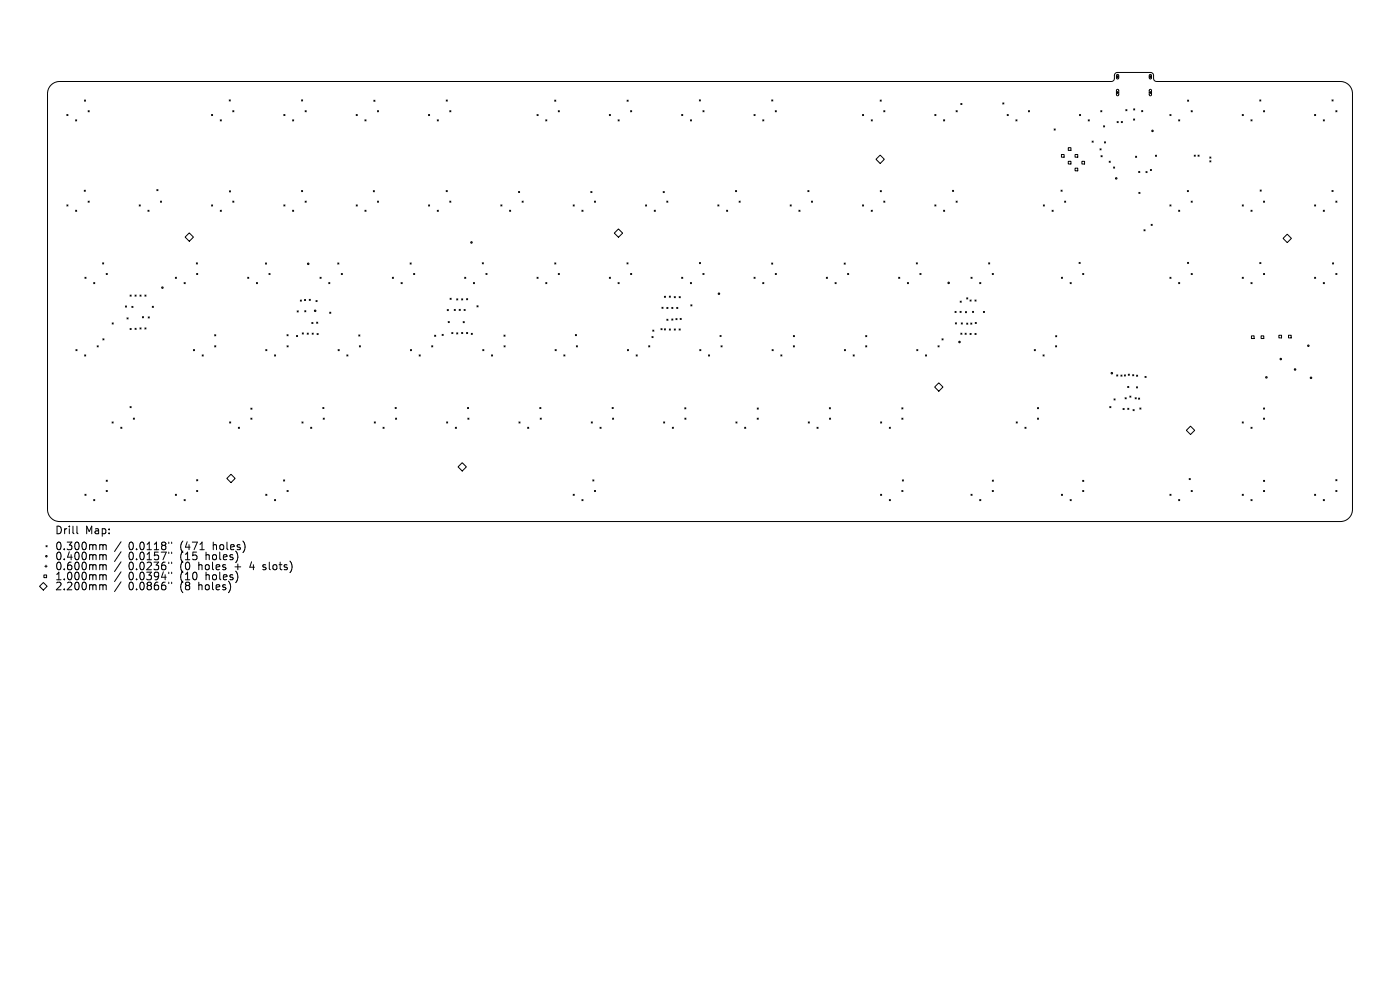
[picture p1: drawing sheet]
<svg xmlns="http://www.w3.org/2000/svg" width="297mm" height="210mm" viewBox="0 0 297 210" stroke-linecap="round" stroke-linejoin="round" font-family="sans-serif">
<defs><g id="words">
<g font-size="2.2">
<text x="11.6" y="113.5">Drill</text>
<text x="18.1" y="113.5">Map:</text>
<text x="11.6" y="116.9">0.300mm</text>
<text x="11.6" y="119">0.400mm</text>
<text x="27.3" y="116.9">0.0118&quot;</text>
<text x="27.3" y="119">0.0157&quot;</text>
<text x="38.3" y="116.9">(471</text>
<text x="38.3" y="119">(15</text>
<text x="43.9" y="119">holes)</text>
<text x="45.4" y="116.9">holes)</text>
<text x="11.6" y="121.2">0.600mm</text>
<text x="11.6" y="123.3">1.000mm</text>
<text x="11.6" y="125.4">2.200mm</text>
<text x="27.3" y="121.2">0.0236&quot;</text>
<text x="27.3" y="123.3">0.0394&quot;</text>
<text x="27.3" y="125.4">0.0866&quot;</text>
<text x="38.3" y="121.2">(0</text>
<text x="38.3" y="123.3">(10</text>
<text x="38.3" y="125.4">(8</text>
<text x="42.3" y="121.2">holes</text>
<text x="42.3" y="125.4">holes)</text>
<text x="43.9" y="123.3">holes)</text>
<text x="50.2" y="121.2">+</text>
<text x="53.5" y="121.2">4</text>
<text x="56.5" y="121.2">slots)</text>
</g>
</g></defs>
<g fill="none" stroke="#000" stroke-width=".21">
<path d="M10.8 18l.7-.5 1.1-.2h223.2l.5-.4 .3-1.3 .5-.2h7.1l.5 .3 .1 1.2 .6 .4h39a2.56 2.56 0 0 1 2.5 2.5v88.3a2.56 2.56 0 0 1-2.5 2.5h-271.8a2.56 2.56 0 0 1-2.5-2.5v-88.3l.1-.8zM236.8 16.3h.5M236.8 19.6h.5M236.9 15.9l.3-.1 .1 .2v.6l-.1 .1-.3-.1zM236.9 19h.3l.1 .2v.9l-.2 .2-.2-.2zM237.1 16v.5M237.1 19.4v.5M243.8 16.3h.5M243.8 19.6h.5M243.9 15.9l.2-.1 .2 .2v.6l-.2 .1-.3-.1zM243.9 19h.2l.2 .2v.9l-.2 .2-.3-.2zM244 16v.5"/>
<path d="M244 19.4v.5M14.2 24.3l.2 .2M14.4 24.3l-.2 .2M16 25.4l.3 .3M16.3 25.4l-.3 .3M17.9 21.2l.3 .3M18.2 21.2l-.3 .3M18.7 23.5l.2 .2M18.9 23.5l-.2 .2M44.9 24.3l.2 .2M45.1 24.3l-.2 .2M46.7 25.4l.3 .3"/>
<path d="M47 25.4l-.3 .3M48.6 21.2l.3 .2M48.9 21.2l-.3 .2M49.4 23.5l.2 .2M49.6 23.5l-.2 .2M60.2 24.3l.3 .2M60.5 24.3l-.3 .2M62.1 25.4l.2 .3M62.3 25.4l-.2 .3M64 21.2l.2 .2M64.2 21.2l-.2 .2M64.7 23.5l.3 .2"/>
<path d="M65 23.5l-.3 .2M75.6 24.3l.2 .2M75.8 24.3l-.2 .2M77.4 25.4l.3 .3M77.7 25.4l-.3 .3M79.3 21.3l.3 .2M79.6 21.3l-.3 .2M80.1 23.5l.2 .2M80.3 23.5l-.2 .2M90.9 24.3l.2 .2M91.1 24.3l-.2 .2M92.8 25.4l.2 .3"/>
<path d="M93 25.4l-.2 .3M94.7 21.2l.2 .3M94.9 21.2l-.2 .3M95.4 23.5l.3 .2M95.7 23.5l-.3 .2M113.9 24.3l.3 .2M114.2 24.3l-.3 .2M115.8 25.4l.2 .3M116 25.4l-.2 .3M117.7 21.2l.2 .3M117.9 21.2l-.2 .3M118.4 23.5l.3 .2"/>
<path d="M118.7 23.5l-.3 .2M129.3 24.3l.2 .2M129.5 24.3l-.2 .2M131.1 25.4l.3 .3M131.4 25.4l-.3 .3M133 21.2l.3 .3M133.3 21.2l-.3 .3M133.8 23.5l.2 .2M134 23.5l-.2 .2M144.6 24.3l.3 .2M144.9 24.3l-.3 .2M146.5 25.4l.2 .3"/>
<path d="M146.7 25.4l-.2 .3M148.4 21.2l.2 .2M148.6 21.2l-.2 .2M149.1 23.5l.3 .2M149.4 23.5l-.3 .2M160 24.3l.2 .2M160.2 24.3l-.2 .2M161.8 25.4l.2 .3M162 25.4l-.2 .3M163.7 21.2l.3 .2M164 21.2l-.3 .2M164.5 23.5l.2 .2"/>
<path d="M164.7 23.5l-.2 .2M183 24.3l.2 .2M183.2 24.3l-.2 .2M184.8 25.4l.3 .3M185.1 25.4l-.3 .3M185.8 33.8l.9-.9 .9 .9-.9 .9zM186.7 21.2l.3 .3M187 21.2l-.3 .3M187.5 23.5l.2 .2M187.7 23.5l-.2 .2M198.3 24.3l.3 .2M198.6 24.3l-.3 .2"/>
<path d="M200.2 25.4l.2 .3M200.4 25.4l-.2 .3M202.8 23.5l.3 .2M203.1 23.5l-.3 .2M203.8 21.9l.3 .3M204.1 21.9l-.3 .3M212.7 21.8l.3 .3M213 21.8l-.3 .3M213.7 24.3l.2 .2M213.9 24.3l-.2 .2M215.5 25.4l.3 .3M215.8 25.4l-.3 .3"/>
<path d="M218.2 23.5l.2 .2M218.4 23.5l-.2 .2M223.6 27.4l.3 .2M223.9 27.4l-.3 .2M225.2 32.8h.5v.5h-.5zM226.6 31.3h.6v.6h-.6zM226.6 34.2h.6v.6h-.6zM228.1 32.8h.5v.5h-.5zM228.1 35.7h.5v.5h-.5zM229 24.3l.2 .2M229.2 24.3l-.2 .2M229.5 34.2h.6v.6h-.6z"/>
<path d="M230.9 25.4l.2 .3M231.1 25.4l-.2 .3M231.7 29.9l.2 .3M231.9 29.9l-.2 .3M233.4 31.6l.2 .2M233.5 23.5l.3 .2M233.6 33l.2 .3M233.6 31.6l-.2 .2M233.8 23.5l-.3 .2M233.8 33l-.2 .3M234.1 26.7l.2 .2M234.3 30.1l.2 .2"/>
<path d="M234.3 26.7l-.2 .2M234.5 30.1l-.2 .2M235.3 34.2l.2 .2M235.5 34.2l-.2 .2M236.2 35.4l.3 .3M236.5 35.4l-.3 .3M237 25.8l.2 .2M237.2 25.8l-.2 .2M237.9 25.8l.2 .2M238.1 25.8l-.2 .2M238.8 23.3l.3 .2M239.1 23.3l-.3 .2"/>
<path d="M240.5 25.2l.2 .3M240.5 23.1l.2 .2M240.7 25.2l-.2 .3M240.7 23.1l-.2 .2M240.9 33.1l.2 .3M241.1 33.1l-.2 .3M241.6 36.4l.2 .2M241.8 36.4l-.2 .2M242.2 23.5l.2 .2M242.4 23.5l-.2 .2M243.1 36.4l.3 .2M243.4 36.4l-.3 .2"/>
<path d="M244 35.9l.3 .3M244.3 35.9l-.3 .3M245.1 32.9l.3 .3M245.4 32.9l-.3 .3M248.2 24.3l.2 .2M248.4 24.3l-.2 .2M250 25.4l.3 .3M250.3 25.4l-.3 .3M251.9 21.2l.3 .3M252.2 21.2l-.3 .3M252.7 23.5l.2 .2M252.9 23.5l-.2 .2"/>
<path d="M253.3 32.9l.3 .2M253.6 32.9l-.3 .2M254.2 32.9l.2 .2M254.4 32.9l-.2 .2M256.6 33.3l.3 .2M256.6 34.1l.3 .3M256.9 33.3l-.3 .2M256.9 34.1l-.3 .3M263.5 24.3l.3 .2M263.8 24.3l-.3 .2M265.4 25.4l.2 .3M265.6 25.4l-.2 .3"/>
<path d="M267.2 21.2l.3 .2M267.5 21.2l-.3 .2M268 23.5l.3 .2M268.3 23.5l-.3 .2M278.9 24.3l.2 .2M279.1 24.3l-.2 .2M280.7 25.4l.3 .3M281 25.4l-.3 .3M282.6 21.2l.2 .2M282.8 21.2l-.2 .2M283.4 23.5l.2 .2M283.6 23.5l-.2 .2"/>
<path d="M14.2 43.5l.2 .2M14.4 43.5l-.2 .2M16 44.6l.3 .2M16.3 44.6l-.3 .2M17.9 40.3l.2 .3M18 58.8l.3 .3M18.1 40.3l-.2 .3M18.3 58.8l-.3 .3M18.7 42.7l.2 .2M18.9 42.7l-.2 .2M19.9 59.9l.2 .3M20.1 59.9l-.2 .3"/>
<path d="M21.8 55.8l.2 .2M22 55.8l-.2 .2M22.5 58l.3 .2M22.8 58l-.3 .2M29.5 43.5l.3 .2M29.8 43.5l-.3 .2M31.4 44.6l.2 .2M31.6 44.6l-.2 .2M33.3 40.2l.2 .3M33.5 40.2l-.2 .3M34 42.7l.3 .2M34.3 42.7l-.3 .2"/>
<path d="M37.2 58.8l.2 .3M37.4 58.8l-.2 .3M39.1 59.9l.2 .3M39.3 59.9l-.2 .3M40.2 49.4l.8 .9-.8 .9-.9-.9zM41.6 55.8l.3 .2M41.7 58l.3 .2M41.9 55.8l-.3 .2M42 58l-.3 .2M44.9 43.5l.2 .2M45.1 43.5l-.2 .2M46.7 44.6l.3 .2"/>
<path d="M47 44.6l-.3 .2M48.7 40.5l.2 .2M48.9 40.5l-.2 .2M49.4 42.7l.2 .2M49.6 42.7l-.2 .2M52.5 58.8l.3 .3M52.8 58.8l-.3 .3M54.4 59.9l.2 .3M54.6 59.9l-.2 .3M56.3 55.8l.2 .2M56.5 55.8l-.2 .2M57.1 58l.2 .2"/>
<path d="M57.3 58l-.2 .2M60.2 43.5l.3 .2M60.5 43.5l-.3 .2M62.1 44.6l.2 .2M62.3 44.6l-.2 .2M64 40.4l.2 .3M64.2 40.4l-.2 .3M64.7 42.7l.3 .2M65 42.7l-.3 .2M67.9 58.8l.2 .3M68.1 58.8l-.2 .3M69.7 59.9l.3 .3"/>
<path d="M70 59.9l-.3 .3M71.7 55.8l.2 .2M71.9 55.8l-.2 .2M72.4 58l.2 .2M72.6 58l-.2 .2M75.6 43.5l.2 .2M75.8 43.5l-.2 .2M77.4 44.6l.3 .2M77.7 44.6l-.3 .2M79.2 40.4l.2 .3M79.4 40.4l-.2 .3M80.1 42.7l.2 .2"/>
<path d="M80.3 42.7l-.2 .2M83.2 58.8l.3 .3M83.5 58.8l-.3 .3M85.1 59.9l.2 .3M85.3 59.9l-.2 .3M87 55.8l.2 .2M87.2 55.8l-.2 .2M87.7 58l.3 .2M88 58l-.3 .2M90.9 43.5l.2 .2M91.1 43.5l-.2 .2M92.8 44.6l.2 .2"/>
<path d="M93 44.6l-.2 .2M94.7 40.4l.2 .3M94.9 40.4l-.2 .3M95.4 42.7l.3 .2M95.7 42.7l-.3 .2M98.6 58.8l.2 .3M98.8 58.8l-.2 .3M100.4 59.9l.3 .3M100.7 59.9l-.3 .3M102.3 55.7l.3 .3M102.6 55.7l-.3 .3M103.1 58l.2 .2"/>
<path d="M103.3 58l-.2 .2M106.2 43.5l.3 .2M106.5 43.5l-.3 .2M108.1 44.6l.2 .2M108.3 44.6l-.2 .2M110 40.6l.2 .3M110.2 40.6l-.2 .3M110.8 42.7l.2 .2M111 42.7l-.2 .2M113.9 58.8l.3 .3M114.2 58.8l-.3 .3M115.8 59.9l.2 .3"/>
<path d="M116 59.9l-.2 .3M117.7 55.8l.2 .2M117.9 55.8l-.2 .2M118.4 58l.3 .2M118.7 58l-.3 .2M121.6 43.5l.2 .2M121.8 43.5l-.2 .2M123.4 44.6l.3 .2M123.7 44.6l-.3 .2M125.3 40.6l.3 .3M125.6 40.6l-.3 .3M126.1 42.7l.2 .2"/>
<path d="M126.3 42.7l-.2 .2M129.3 58.8l.2 .3M129.5 58.8l-.2 .3M131.1 59.9l.3 .3M131.2 48.6l.9 .8-.9 .9-.9-.9zM131.4 59.9l-.3 .3M133 55.8l.2 .2M133.2 55.8l-.2 .2M133.8 58l.2 .2M134 58l-.2 .2M136.9 43.5l.3 .2M137.2 43.5l-.3 .2"/>
<path d="M138.8 44.6l.2 .2M139 44.6l-.2 .2M140.7 40.6l.2 .3M140.9 40.6l-.2 .3M141.4 42.7l.3 .2M141.7 42.7l-.3 .2M144.6 58.8l.3 .3M144.9 58.8l-.3 .3M146.5 59.9l.2 .3M146.7 59.9l-.2 .3M148.4 55.7l.2 .2M148.6 55.7l-.2 .2"/>
<path d="M149.1 58l.3 .2M149.4 58l-.3 .2M152.3 43.5l.2 .2M152.5 43.5l-.2 .2M154.1 44.6l.3 .2M154.4 44.6l-.3 .2M156 40.4l.3 .3M156.3 40.4l-.3 .3M156.8 42.7l.2 .2M157 42.7l-.2 .2M160 58.8l.2 .3M160.2 58.8l-.2 .3"/>
<path d="M161.8 59.9l.2 .3M162 59.9l-.2 .3M163.7 55.8l.2 .2M163.9 55.8l-.2 .2M164.5 58l.2 .2M164.7 58l-.2 .2M167.6 43.5l.3 .2M167.9 43.5l-.3 .2M169.5 44.6l.2 .2M169.7 44.6l-.2 .2M171.4 40.4l.2 .3M171.6 40.4l-.2 .3"/>
<path d="M172.1 42.7l.3 .2M172.4 42.7l-.3 .2M175.3 58.8l.2 .3M175.5 58.8l-.2 .3M177.2 59.9l.2 .3M177.4 59.9l-.2 .3M179.1 55.8l.2 .2M179.3 55.8l-.2 .2M179.8 58l.3 .2M180.1 58l-.3 .2M183 43.5l.2 .2M183.2 43.5l-.2 .2"/>
<path d="M184.8 44.6l.3 .2M185.1 44.6l-.3 .2M186.7 40.4l.3 .3M187 40.4l-.3 .3M187.5 42.7l.2 .2M187.7 42.7l-.2 .2M190.6 58.8l.3 .3M190.9 58.8l-.3 .3M192.5 59.9l.2 .3M192.7 59.9l-.2 .3M194.4 55.8l.2 .2M194.6 55.8l-.2 .2"/>
<path d="M195.2 58l.2 .2M195.4 58l-.2 .2M198.3 43.5l.3 .2M198.6 43.5l-.3 .2M200.2 44.6l.2 .2M200.4 44.6l-.2 .2M202.1 40.4l.2 .2M202.3 40.4l-.2 .2M202.8 42.7l.3 .2M203.1 42.7l-.3 .2M206 58.8l.2 .3M206.2 58.8l-.2 .3"/>
<path d="M207.8 59.9l.3 .3M208.1 59.9l-.3 .3M209.7 55.8l.3 .2M210 55.8l-.3 .2M210.5 58l.2 .2M210.7 58l-.2 .2M221.3 43.5l.3 .2M221.6 43.5l-.3 .2M223.2 44.6l.2 .2M223.4 44.6l-.2 .2M225.1 40.3l.2 .3M225.2 58.8l.2 .3"/>
<path d="M225.3 40.3l-.2 .3M225.4 58.8l-.2 .3M225.8 42.7l.3 .2M226.1 42.7l-.3 .2M227 59.9l.3 .3M227.3 59.9l-.3 .3M228.9 55.7l.3 .2M229.2 55.7l-.3 .2M229.7 58l.2 .2M229.9 58l-.2 .2M241.6 40.8l.2 .2M241.8 40.8l-.2 .2"/>
<path d="M242.7 48.7l.2 .3M242.9 48.7l-.2 .3M244.2 47.6l.2 .2M244.4 47.6l-.2 .2M248.2 43.5l.2 .2M248.2 58.8l.2 .3M248.4 43.5l-.2 .2M248.4 58.8l-.2 .3M250 44.6l.3 .2M250 59.9l.3 .3M250.3 44.6l-.3 .2M250.3 59.9l-.3 .3"/>
<path d="M251.9 40.4l.2 .3M251.9 55.7l.3 .2M252.1 40.4l-.2 .3M252.2 55.7l-.3 .2M252.7 42.7l.2 .2M252.7 58l.2 .2M252.9 42.7l-.2 .2M252.9 58l-.2 .2M263.5 43.5l.3 .2M263.5 58.8l.3 .3M263.8 43.5l-.3 .2M263.8 58.8l-.3 .3"/>
<path d="M265.4 44.6l.2 .2M265.4 59.9l.2 .3M265.6 44.6l-.2 .2M265.6 59.9l-.2 .3M267.3 55.7l.2 .2M267.3 40.3l.3 .2M267.5 55.7l-.2 .2M267.6 40.3l-.3 .2M268 42.7l.3 .2M268 58l.3 .2M268.3 42.7l-.3 .2M268.3 58l-.3 .2"/>
<path d="M272.2 50.6l.9-.9 .9 .9-.9 .9zM278.9 43.5l.2 .2M278.9 58.8l.2 .3M279.1 43.5l-.2 .2M279.1 58.8l-.2 .3M280.7 44.6l.3 .2M280.7 59.9l.3 .3M281 44.6l-.3 .2M281 59.9l-.3 .3M282.6 40.4l.2 .2M282.7 55.8l.2 .2M282.8 40.4l-.2 .2"/>
<path d="M282.9 55.8l-.2 .2M283.4 58l.2 .2M283.4 42.7l.2 .2M283.6 42.7l-.2 .2M283.6 58l-.2 .2M16.1 74.2l.2 .2M16.3 74.2l-.2 .2M18 75.3l.2 .2M18.2 75.3l-.2 .2M20.6 73.4l.3 .2M20.9 73.4l-.3 .2M21.8 71.9l.3 .2"/>
<path d="M22.1 71.9l-.3 .2M23.8 68.5l.2 .2M24 68.5l-.2 .2M26.6 64.9l.2 .2M26.8 64.9l-.2 .2M26.9 67.4l.3 .3M27.2 67.4l-.3 .3M27.6 62.6l.2 .2M27.6 69.7l.2 .2M27.8 62.6l-.2 .2M27.8 69.7l-.2 .2M28 65l.2 .2"/>
<path d="M28.2 65l-.2 .2M28.6 62.6l.3 .2M28.6 69.6l.3 .3M28.9 62.6l-.3 .2M28.9 69.6l-.3 .3M29.7 62.6l.2 .2M29.7 69.6l.2 .2M29.9 62.6l-.2 .2M29.9 69.6l-.2 .2M30.2 67.2l.3 .2M30.5 67.2l-.3 .2M30.7 62.6l.3 .2"/>
<path d="M30.7 69.6l.3 .2M31 62.6l-.3 .2M31 69.6l-.3 .2M31.4 67.2l.3 .3M31.7 67.2l-.3 .3M32.3 65l.2 .2M32.5 65l-.2 .2M41 74.2l.3 .2M41.3 74.2l-.3 .2M42.9 75.3l.2 .2M43.1 75.3l-.2 .2M45.5 71l.3 .2"/>
<path d="M45.5 73.4l.3 .2M45.8 71l-.3 .2M45.8 73.4l-.3 .2M56.4 74.2l.2 .2M56.6 74.2l-.2 .2M58.2 75.3l.3 .2M58.5 75.3l-.3 .2M60.9 71l.2 .2M60.9 73.4l.2 .2M61.1 71l-.2 .2M61.1 73.4l-.2 .2M62.9 71.2l.2 .2"/>
<path d="M63 65.9l.3 .3M63.1 71.2l-.2 .2M63.3 65.9l-.3 .3M63.7 63.7l.3 .2M64 63.7l-.3 .2M64.1 70.6l.3 .3M64.4 70.6l-.3 .3M64.6 63.5l.2 .3M64.6 65.9l.3 .3M64.8 63.5l-.2 .3M64.9 65.9l-.3 .3M65.2 70.7l.2 .2"/>
<path d="M65.4 70.7l-.2 .2M65.6 63.5l.2 .2M65.8 63.5l-.2 .2M66.2 68.4l.2 .2M66.2 70.7l.3 .2M66.4 68.4l-.2 .2M66.5 70.7l-.3 .2M67 63.7l.3 .3M67.2 68.3l.2 .3M67.3 70.7l.2 .3M67.3 63.7l-.3 .3M67.4 68.3l-.2 .3"/>
<path d="M67.5 70.7l-.2 .3M69.9 66.2l.3 .3M70.2 66.2l-.3 .3M71.7 74.2l.3 .2M72 74.2l-.3 .2M73.6 75.3l.2 .2M73.8 75.3l-.2 .2M76.1 71l.2 .3M76.2 73.4l.3 .2M76.3 71l-.2 .3M76.5 73.4l-.3 .2M87.1 74.2l.2 .2"/>
<path d="M87.3 74.2l-.2 .2M88.9 75.3l.3 .2M89.2 75.3l-.3 .2M91.6 73.4l.2 .2M91.8 73.4l-.2 .2M92.2 71.1l.2 .2M92.4 71.1l-.2 .2M93.8 70.9l.2 .3M94 70.9l-.2 .3M94.9 65.7l.2 .2M95.1 68.2l.2 .2M95.1 65.7l-.2 .2"/>
<path d="M95.3 68.2l-.2 .2M95.5 63.3l.2 .2M95.7 63.3l-.2 .2M95.8 70.5l.3 .3M96.1 70.5l-.3 .3M96.4 65.6l.2 .3M96.6 65.6l-.2 .3M96.9 63.4l.2 .2M96.9 70.6l.2 .2M97.1 63.4l-.2 .2M97.1 70.6l-.2 .2M97.4 65.6l.2 .3"/>
<path d="M97.6 65.6l-.2 .3M97.9 63.4l.3 .2M97.9 70.5l.3 .3M98.2 63.4l-.3 .2M98.2 70.5l-.3 .3M98.3 68.2l.2 .3M98.5 65.6l.2 .3M98.5 68.2l-.2 .3M98.7 65.6l-.2 .3M99 63.4l.2 .2M99 70.5l.2 .3M99.2 63.4l-.2 .2"/>
<path d="M99.2 70.5l-.2 .3M100 70.7l.2 .2M100.2 70.7l-.2 .2M101.2 64.9l.2 .2M101.4 64.9l-.2 .2M102.4 74.2l.3 .2M102.7 74.2l-.3 .2M104.3 75.3l.2 .2M104.5 75.3l-.2 .2M106.9 71.1l.3 .2M106.9 73.4l.3 .2M107.2 71.1l-.3 .2"/>
<path d="M107.2 73.4l-.3 .2M117.8 74.2l.2 .2M118 74.2l-.2 .2M119.6 75.3l.3 .2M119.9 75.3l-.3 .2M122.1 71l.2 .2M122.3 73.4l.2 .2M122.3 71l-.2 .2M122.5 73.4l-.2 .2M133.1 74.2l.2 .2M133.3 74.2l-.2 .2M135 75.3l.2 .2"/>
<path d="M135.2 75.3l-.2 .2M137.6 73.4l.3 .2M137.9 73.4l-.3 .2M138.3 71.4l.2 .2M138.5 70l.2 .3M138.5 71.4l-.2 .2M138.7 70l-.2 .3M140.2 69.7l.3 .2M140.4 65.2l.3 .2M140.5 69.7l-.3 .2M140.7 65.2l-.3 .2M140.9 69.8l.3 .2"/>
<path d="M140.9 62.8l.3 .3M141.2 62.8l-.3 .3M141.2 69.8l-.3 .2M141.5 65.2l.2 .2M141.5 67.7l.2 .3M141.7 65.2l-.2 .2M141.7 67.7l-.2 .3M142 62.8l.2 .3M142 69.8l.2 .2M142.2 62.8l-.2 .3M142.2 69.8l-.2 .2M142.5 65.2l.3 .2"/>
<path d="M142.5 67.7l.3 .2M142.8 67.7l-.3 .2M142.8 65.2l-.3 .2M143 62.9l.3 .3M143 69.8l.3 .2M143.3 62.9l-.3 .3M143.3 69.8l-.3 .2M143.4 67.6l.2 .2M143.6 65.2l.2 .2M143.6 67.6l-.2 .2M143.8 65.2l-.2 .2M144.1 69.8l.2 .2"/>
<path d="M144.1 62.9l.2 .3M144.3 67.5l.2 .3M144.3 69.8l-.2 .2M144.3 62.9l-.2 .3M144.5 67.5l-.2 .3M146.6 64.7l.2 .2M146.8 64.7l-.2 .2M148.4 74.2l.3 .2M148.7 74.2l-.3 .2M150.3 75.3l.2 .2M150.5 75.3l-.2 .2M152.7 71.2l.3 .2"/>
<path d="M153 73.4l.2 .2M153 71.2l-.3 .2M153.2 73.4l-.2 .2M163.8 74.2l.2 .2M164 74.2l-.2 .2M165.6 75.3l.3 .2M165.9 75.3l-.3 .2M168.3 73.4l.2 .2M168.3 71.2l.2 .2M168.5 73.4l-.2 .2M168.5 71.2l-.2 .2M179.1 74.2l.3 .2"/>
<path d="M179.4 74.2l-.3 .2M181 75.3l.2 .2M181.2 75.3l-.2 .2M183.6 73.4l.3 .2M183.6 71.2l.3 .2M183.9 73.4l-.3 .2M183.9 71.2l-.3 .2M194.5 74.2l.2 .2M194.7 74.2l-.2 .2M196.3 75.3l.3 .2M196.6 75.3l-.3 .2M199 73.4l.2 .2"/>
<path d="M199.2 73.4l-.2 .2M199.8 71.9l.3 .2M200.1 71.9l-.3 .2M202.6 66.1l.2 .2M202.7 68.5l.2 .2M202.8 66.1l-.2 .2M202.9 68.5l-.2 .2M203.7 66l.2 .3M203.7 63.9l.2 .2M203.8 70.7l.3 .2M203.9 66l-.2 .3M203.9 68.5l.3 .2"/>
<path d="M203.9 63.9l-.2 .2M204.1 70.7l-.3 .2M204.2 68.5l-.3 .2M204.7 70.7l.3 .2M204.8 66.1l.2 .2M205 70.7l-.3 .2M205 66.1l-.2 .2M205.1 63.2l.2 .2M205.1 68.5l.2 .3M205.3 63.2l-.2 .2M205.3 68.5l-.2 .3M205.8 63.6l.2 .3"/>
<path d="M205.8 70.7l.2 .3M205.9 68.5l.3 .3M206 63.6l-.2 .3M206 70.7l-.2 .3M206.2 68.5l-.3 .3M206.3 66l.2 .3M206.5 66l-.2 .3M206.8 70.7l.3 .3M206.8 63.6l.3 .3M206.9 68.4l.2 .2M207.1 70.7l-.3 .3M207.1 63.6l-.3 .3"/>
<path d="M207.1 68.4l-.2 .2M208.6 66.1l.3 .2M208.9 66.1l-.3 .2M219.4 74.2l.3 .2M219.7 74.2l-.3 .2M221.3 75.3l.2 .2M221.5 75.3l-.2 .2M223.9 73.4l.3 .2M223.9 71.2l.3 .2M224.2 73.4l-.3 .2M224.2 71.2l-.3 .2M236.9 79.5l.2 .3"/>
<path d="M237.1 79.5l-.2 .3M237.8 79.6l.2 .2M238 79.6l-.2 .2M238.5 79.5l.3 .3M238.8 79.5l-.3 .3M239.4 79.4l.2 .2M239.6 79.4l-.2 .2M240.3 79.5l.2 .2M240.5 79.5l-.2 .2M241.1 79.6l.3 .2M241.4 79.6l-.3 .2M242.9 79.8l.2 .3"/>
<path d="M243.1 79.8l-.2 .3M265.5 71.2h.6v.6h-.6zM267.5 71.2h.6v.6h-.6zM271.3 71.1h.6v.6h-.6zM273.3 71.1h.6v.6h-.6zM23.8 89.5l.2 .2M24 89.5l-.2 .2M25.6 90.6l.3 .3M25.9 90.6l-.3 .3M27.6 86.2l.2 .3M27.8 86.2l-.2 .3M28.3 88.7l.2 .2"/>
<path d="M28.5 88.7l-.2 .2M48.7 89.5l.2 .2M48.9 89.5l-.2 .2M50.6 90.6l.2 .3M50.8 90.6l-.2 .3M53.2 88.7l.3 .2M53.2 86.6l.3 .2M53.5 88.7l-.3 .2M53.5 86.6l-.3 .2M64.1 89.5l.2 .2M64.3 89.5l-.2 .2M65.9 90.6l.2 .3"/>
<path d="M66.1 90.6l-.2 .3M68.5 86.4l.2 .3M68.6 88.7l.2 .2M68.7 86.4l-.2 .3M68.8 88.7l-.2 .2M79.4 89.5l.2 .2M79.6 89.5l-.2 .2M81.2 90.6l.3 .3M81.5 90.6l-.3 .3M83.8 86.4l.3 .3M83.9 88.7l.2 .2M84.1 86.4l-.3 .3"/>
<path d="M84.1 88.7l-.2 .2M94.7 89.5l.3 .2M95 89.5l-.3 .2M96.6 90.6l.2 .3M96.8 90.6l-.2 .3M98.1 98.1l.8 .9-.8 .9-.9-.9zM99.2 86.4l.2 .3M99.3 88.7l.2 .2M99.4 86.4l-.2 .3M99.5 88.7l-.2 .2M110.1 89.5l.2 .2M110.3 89.5l-.2 .2"/>
<path d="M111.9 90.6l.3 .3M112.2 90.6l-.3 .3M114.5 86.4l.3 .3M114.6 88.7l.2 .2M114.8 86.4l-.3 .3M114.8 88.7l-.2 .2M125.4 89.5l.3 .2M125.7 89.5l-.3 .2M127.3 90.6l.2 .3M127.5 90.6l-.2 .3M129.9 86.4l.2 .3M129.9 88.7l.3 .2"/>
<path d="M130.1 86.4l-.2 .3M130.2 88.7l-.3 .2M140.8 89.5l.2 .2M141 89.5l-.2 .2M142.6 90.6l.3 .3M142.9 90.6l-.3 .3M145.3 86.5l.2 .2M145.3 88.7l.2 .2M145.5 86.5l-.2 .2M145.5 88.7l-.2 .2M156.1 89.5l.3 .2M156.4 89.5l-.3 .2"/>
<path d="M158 90.6l.2 .3M158.2 90.6l-.2 .3M160.6 88.7l.3 .2M160.6 86.6l.3 .2M160.9 88.7l-.3 .2M160.9 86.6l-.3 .2M171.5 89.5l.2 .2M171.7 89.5l-.2 .2M173.3 90.6l.3 .3M173.6 90.6l-.3 .3M175.9 86.5l.3 .2M176 88.7l.2 .2"/>
<path d="M176.2 86.5l-.3 .2M176.2 88.7l-.2 .2M186.8 89.5l.2 .2M187 89.5l-.2 .2M188.7 90.6l.2 .3M188.9 90.6l-.2 .3M191.3 86.5l.3 .3M191.3 88.7l.3 .2M191.6 86.5l-.3 .3M191.6 88.7l-.3 .2M199.2 81.2l.8 .9-.8 .9-.9-.9zM215.6 89.5l.2 .2"/>
<path d="M215.8 89.5l-.2 .2M217.4 90.6l.3 .3M217.7 90.6l-.3 .3M220.1 86.5l.2 .2M220.1 88.7l.2 .2M220.3 86.5l-.2 .2M220.3 88.7l-.2 .2M235.4 86.2l.3 .3M235.7 86.2l-.3 .3M236.3 84.6l.3 .3M236.6 84.6l-.3 .3M238.2 86.6l.3 .3"/>
<path d="M238.5 86.6l-.3 .3M238.7 84.4l.2 .2M238.9 84.4l-.2 .2M239.2 82l.3 .2M239.2 86.6l.3 .2M239.5 82l-.3 .2M239.5 86.6l-.3 .2M239.7 84l.2 .3M239.9 84l-.2 .3M240.4 86.9l.2 .2M240.6 86.9l-.2 .2M240.8 84.4l.3 .2"/>
<path d="M241.1 84.4l-.3 .2M241.1 82.1l.2 .2M241.3 82.1l-.2 .2M241.5 84.4l.3 .3M241.8 84.4l-.3 .3M241.8 86.5l.2 .3M242 86.5l-.2 .3M251.7 91.3l.9-.9 .9 .9-.9 .9zM263.5 89.5l.3 .2M263.8 89.5l-.3 .2M265.4 90.6l.2 .3M265.6 90.6l-.2 .3"/>
<path d="M268 86.5l.3 .3M268 88.7l.3 .2M268.3 88.7l-.3 .2M268.3 86.5l-.3 .3M9.8 115.7l.2 .3M9.8 119.9v.5M10 115.7l-.2 .3M16.3 111.6v1.4l.2 .2M18 104.8l.3 .3M18.3 104.8l-.3 .3M19.9 106l.2 .2M20.1 106l-.2 .2"/>
<path d="M21.4 115.5l.4 .3M21.4 117.7l.4 .2M21.4 119.8l.4 .2M21.8 115.8l.3-.3 .4 .1v1M21.8 115.8v.8M21.8 117.9v.8M21.8 117.9l.3-.2h.4v1M22.5 101.9l.3 .2M22.5 104l.3 .3M22.8 101.9l-.3 .2M22.8 104l-.3 .3M25.7 114.9l-1.4 2.1"/>
<path d="M25.7 117l-1.4 2.1M25.7 119.2l-1.4 2M35.8 115v.3M35.8 117.1v.3M35.8 119.2v.4M36.4 115v.3M36.4 117.1v.3M36.4 119.2v.4M37.2 104.8l.2 .3M37.4 104.8l-.2 .3M39.1 106l.2 .2M39.3 106l-.2 .2"/>
<path d="M41.7 104l.3 .3M41.7 101.8l.3 .2M42 104l-.3 .3M42 101.8l-.3 .2M42.4 116.6h.9M48.1 101.5l.9-.9 .9 .9-.9 .9zM55.8 119.9v.3M56.4 104.8l.2 .3M56.6 104.8l-.2 .3M58.2 106l.3 .2M58.5 106l-.3 .2M60.2 101.8l.2 .2"/>
<path d="M60.4 101.8l-.2 .2M60.9 104l.2 .3M61.1 104l-.2 .3M121.6 104.8l.2 .3M121.8 104.8l-.2 .3M123.4 106l.3 .2M123.7 106l-.3 .2M125.8 101.8l.2 .2M126 101.8l-.2 .2M126.1 104l.2 .3M126.3 104l-.2 .3M186.8 104.8l.2 .3"/>
<path d="M187 104.8l-.2 .3M188.7 106l.2 .2M188.9 106l-.2 .2M191.3 104l.3 .3M191.4 101.8l.3 .2M191.6 104l-.3 .3M191.7 101.8l-.3 .2M206 104.8l.2 .3M206.2 104.8l-.2 .3M207.8 106l.3 .2M208.1 106l-.3 .2M210.5 104l.2 .3"/>
<path d="M210.5 101.8l.3 .3M210.7 104l-.2 .3M210.8 101.8l-.3 .3M225.2 104.8l.2 .3M225.4 104.8l-.2 .3M227 106l.3 .2M227.3 106l-.3 .2M229.7 101.9l.2 .2M229.7 104l.2 .3M229.9 101.9l-.2 .2M229.9 104l-.2 .3M248.2 104.8l.2 .3"/>
<path d="M248.4 104.8l-.2 .3M250 106l.3 .2M250.3 106l-.3 .2M252.3 101.5l.2 .2M252.5 101.5l-.2 .2M252.7 104l.2 .3M252.9 104l-.2 .3M263.5 104.8l.3 .3M263.8 104.8l-.3 .3M265.4 106l.2 .2M265.6 106l-.2 .2M268 104l.3 .3"/>
<path d="M268 101.9l.3 .2M268.3 104l-.3 .3M268.3 101.9l-.3 .2M278.9 104.8l.2 .3M279.1 104.8l-.2 .3M280.7 106l.3 .2M281 106l-.3 .2M283.4 104l.2 .3M283.4 101.7l.2 .3M283.6 104l-.2 .3M283.6 101.7l-.2 .3M9.2 123.6l.8 .8-.8 .8-.8-.8z"/>
<path d="M9.3 122h.6v.5h-.6zM9.5 120.1h.5M21.4 121.9l.4 .2M21.4 124l.4 .3M21.8 120v.9M21.8 122.1v.9M21.8 124.3v.8M21.8 120l.3-.2 .4 .1v1M21.8 122.1l.3-.2 .4 .1v1M21.8 124.3l.3-.3 .4 .1v1M25.7 121.3l-1.4 2.1M25.7 123.4l-1.4 2.1"/>
<path d="M35.8 121.4v.3M35.8 123.5v.3M36.4 121.4v.3M36.4 123.5v.3M55.8 120.8l.1 .1"/>
<circle cx="236.8" cy="37.8" r=".16"/>
<circle cx="244.5" cy="27.8" r=".16"/>
<circle cx="65.4" cy="56" r=".16"/>
<circle cx="100" cy="51.4" r=".16"/>
<circle cx="34.5" cy="61" r=".16"/>
<circle cx="66.9" cy="65.9" r=".16"/>
<circle cx="152.5" cy="62.3" r=".16"/>
<circle cx="201.3" cy="60" r=".16"/>
<circle cx="203.6" cy="72.5" r=".16"/>
<circle cx="235.9" cy="79.2" r=".16"/>
<circle cx="271.7" cy="76.2" r=".16"/>
<circle cx="274.7" cy="78.4" r=".16"/>
<circle cx="277.6" cy="73.3" r=".16"/>
<circle cx="268.7" cy="80" r=".16"/>
<circle cx="278.1" cy="80.1" r=".16"/>
<circle cx="9.8" cy="118" r=".16"/>
</g>
<use href="#words"/>
</svg>
